###############################################################
#  Generated by:      Cadence Innovus 20.13-s083_1
#  OS:                Linux x86_64(Host ID rice-503-20-north)
#  Generated on:      Fri May  6 19:49:47 2022
#  Design:            ringosc
#  Command:           write_lef_abstract -specifyTopLayer 6 -PGPinLayers {5 6} -noCutObs -stripePin results/ringosc.lef
###############################################################

VERSION 5.8 ;

BUSBITCHARS "[]" ;
DIVIDERCHAR "/" ;

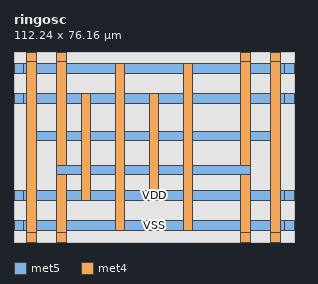
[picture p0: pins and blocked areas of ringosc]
MACRO ringosc
  CLASS BLOCK ;
  SIZE 112.240000 BY 76.160000 ;
  FOREIGN ringosc 0.000000 0.000000 ;
  ORIGIN 0 0 ;
  SYMMETRY X Y R90 ;
  PIN VSS
    DIRECTION INOUT ;
    USE GROUND ;
    PORT
      LAYER met5 ;
        RECT 108.240000 67.360000 112.240000 71.360000 ;
    END
    PORT
      LAYER met5 ;
        RECT 0.000000 67.360000 4.000000 71.360000 ;
    END
    PORT
      LAYER met5 ;
        RECT 108.240000 4.560000 112.240000 8.560000 ;
    END
    PORT
      LAYER met5 ;
        RECT 0.000000 4.560000 4.000000 8.560000 ;
    END
    PORT
      LAYER met4 ;
        RECT 102.880000 72.160000 106.880000 76.160000 ;
    END
    PORT
      LAYER met4 ;
        RECT 102.880000 0.000000 106.880000 4.000000 ;
    END
    PORT
      LAYER met4 ;
        RECT 4.980000 72.160000 8.980000 76.160000 ;
    END
    PORT
      LAYER met4 ;
        RECT 4.980000 0.000000 8.980000 4.000000 ;
    END

# P/G power stripe data as pin
    PORT
      LAYER met4 ;
        RECT 68.000000 4.560000 71.360000 71.360000 ;
        RECT 40.800000 4.560000 44.160000 71.360000 ;
        RECT 102.880000 0.000000 106.880000 76.160000 ;
        RECT 4.980000 0.000000 8.980000 76.160000 ;
      LAYER met5 ;
        RECT 0.000000 4.560000 112.240000 8.560000 ;
        RECT 0.000000 67.360000 112.240000 71.360000 ;
        RECT 4.980000 40.800000 106.880000 44.160000 ;
    END
# end of P/G power stripe data as pin

  END VSS
  PIN VDD
    DIRECTION INOUT ;
    USE POWER ;
    PORT
      LAYER met5 ;
        RECT 108.240000 55.360000 112.240000 59.360000 ;
    END
    PORT
      LAYER met5 ;
        RECT 0.000000 55.360000 4.000000 59.360000 ;
    END
    PORT
      LAYER met5 ;
        RECT 108.240000 16.560000 112.240000 20.560000 ;
    END
    PORT
      LAYER met5 ;
        RECT 0.000000 16.560000 4.000000 20.560000 ;
    END
    PORT
      LAYER met4 ;
        RECT 90.880000 72.160000 94.880000 76.160000 ;
    END
    PORT
      LAYER met4 ;
        RECT 90.880000 0.000000 94.880000 4.000000 ;
    END
    PORT
      LAYER met4 ;
        RECT 16.980000 72.160000 20.980000 76.160000 ;
    END
    PORT
      LAYER met4 ;
        RECT 16.980000 0.000000 20.980000 4.000000 ;
    END

# P/G power stripe data as pin
    PORT
      LAYER met4 ;
        RECT 54.400000 16.560000 57.760000 59.360000 ;
        RECT 27.200000 16.560000 30.560000 59.360000 ;
        RECT 90.880000 0.000000 94.880000 76.160000 ;
        RECT 16.980000 0.000000 20.980000 76.160000 ;
      LAYER met5 ;
        RECT 16.980000 27.200000 94.880000 30.560000 ;
        RECT 0.000000 16.560000 112.240000 20.560000 ;
        RECT 0.000000 55.360000 112.240000 59.360000 ;
    END
# end of P/G power stripe data as pin

  END VDD
  OBS
    LAYER li1 ;
      RECT 0.000000 0.000000 112.240000 76.160000 ;
    LAYER met1 ;
      RECT 0.000000 0.000000 112.240000 76.160000 ;
    LAYER met2 ;
      RECT 0.000000 0.000000 112.240000 76.160000 ;
    LAYER met3 ;
      RECT 0.000000 0.000000 112.240000 76.160000 ;
    LAYER met4 ;
      RECT 0.000000 0.000000 112.240000 76.160000 ;
    LAYER met5 ;
      RECT 0.000000 0.000000 112.240000 76.160000 ;
  END
END ringosc

END LIBRARY
